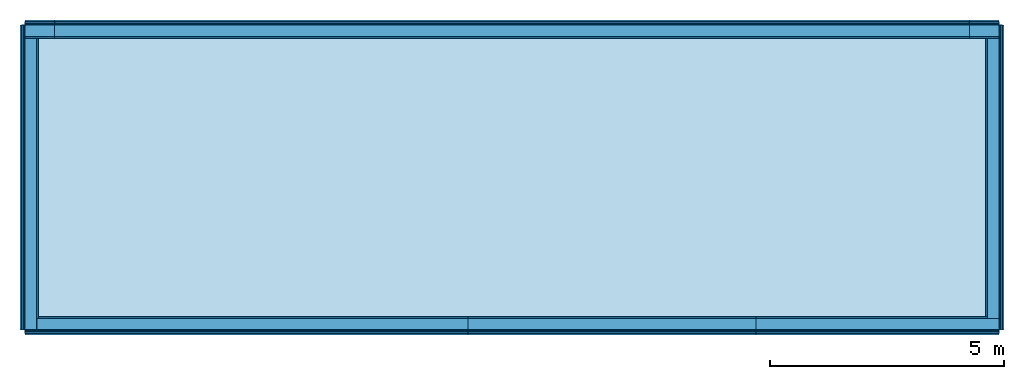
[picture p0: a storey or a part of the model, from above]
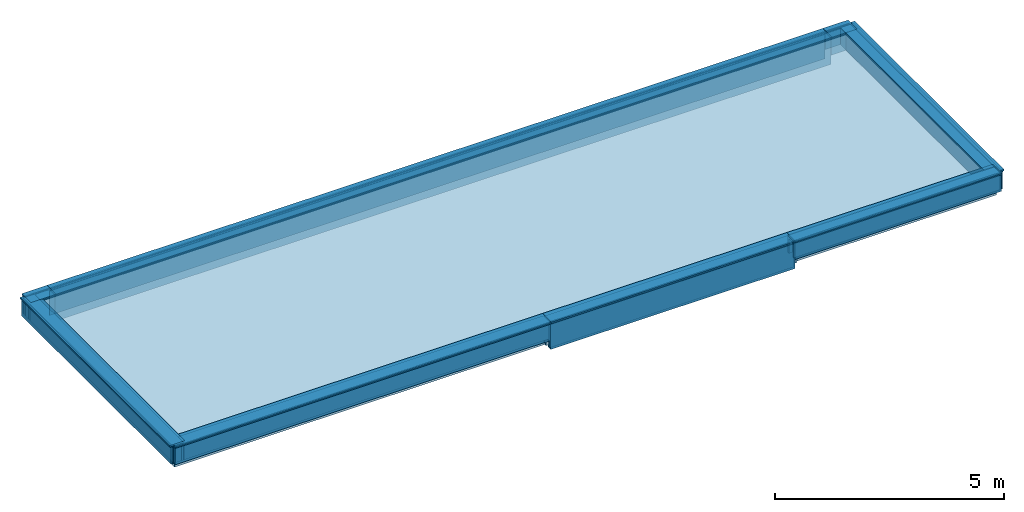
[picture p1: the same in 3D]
Properties of the parts of a building model (IFC2X3)

# File
Description: ViewDefinition [CoordinationView_V2.0], Option [Drawing Scale: 100.000000], Option [Global Unique Identifiers (GUID): Keep existing], Option [Elements to export: Visible elements (on all stories)], Option [Partial Structure Display: Entire Model], Option [IFC Domain: All], Option [Structural Function: All Elements], Option [Convert Grid elements: On], Option [Convert IFC Annotations and ARCHICAD 2D elements: Off], Option [Convert 2D symbols of Doors and Windows: Off], Option [Explode Composite and Complex Profile elements into parts: Off], Option [Export geometries that Participates in Collision Detection only: Off], Option [Multi-skin complex geometries: Building element parts], Option [Elements in Solid Element Operations: Extruded/revolved], Option [Elements with junctions: Extruded/revolved without junctions], Option [Slabs with slanted edge(s): Extruded], Option [Use legacy geometric methods as in Coordination View 1.0: Off], Option [IFC Site Geometry: As boundary representation (BRep)], Option [IFC Site Location: At Project Origin], Option [Curtain Wall export mode: Container Element], Option [Railing export mode: Single Element], Option [Stair export mode: Container Element], Option [Properties To Export: All properties], Option [Space containment: Off], Option [Bounding Box: Off], Option [Geometry to type objects: Off], Option [Element Properties: Off], Option [Property Type Element Parameter: Off], Option [Quantity Type Element Parameter: Off], Option [IFC Base Quantities: Off], Option [Window Door Lining and Panel Parameters: On], Option [IFC Space boundaries: Off], Option [ARCHICAD Zone Categories as IFC Space classification data: Off], Option [Element Classifications: Off]
File name: C:\Users\Thiago Mundim\Desktop\05_01 AC 21\Architectural File_R01.ifc
Time: 2017-08-08T17:24:18
Author: Ideia1 Arquitetura
Organization: Ideia1 Arquitetura
Written by: The EXPRESS Data Manager Version 5.02.0100.09 : 26 Sep 2013
Made in: IFC file generated by GRAPHISOFT ARCHICAD-64 21.0.0 INT FULL Windows version (IFC2x3 add-on version: 3005 INT FULL).
Authorization: Ideia1 Arquitetura

# IfcProject, Grove House
Description: Residential House; Phase: Schematic Design

# IfcSite, Grove Residential
RefLatitude: 24, 28, 0, 0; RefLongitude: 54, 25, 0, 0; RefElevation: 0 mm

# IfcBuildingStorey (4)
In: Building
Name | Elevation (mm)
Basement | -3060
Ground Floor | 0
First Floor | 3740
Roof Level | 6660

# IfcBuildingElementPart (84)
Name | In | Material
5 x Titanium Zinc | Ground Floor | Titanium Zinc
5 x Membrane - Rainproof | Ground Floor | Membrane - Rainproof
5 x Insulation - Plastic Soft | Ground Floor | Insulation - Plastic Soft
5 x Air Space | Ground Floor | Air Space
5 x Cement Board | Ground Floor | Cement Board
5 x External Render | Ground Floor | External Render
Titanium Zinc | First Floor | Titanium Zinc
Membrane - Rainproof | First Floor | Membrane - Rainproof
Insulation - Plastic Soft | First Floor | Insulation - Plastic Soft
Air Space | First Floor | Air Space
Cement Board | First Floor | Cement Board
External Render | First Floor | External Render
8 x Timber - Roof | Roof Level | Timber - Roof
8 x Insulation - Plastic Soft | Roof Level | Insulation - Plastic Soft
8 x Stone - Finish | Roof Level | Stone - Finish
8 x Membrane - Rainproof | Roof Level | Membrane - Rainproof
8 x Timber - External Cladding | Roof Level | Timber - External Cladding
8 x Air Space - Fixing Zone | Roof Level | Air Space - Fixing Zone

# IfcBuildingElementProxy: Fireplace-Traditional 21, FU - 004
In: Ground Floor
Material: Background
AC_Pset_RenovationAndPhasing - Renovation Status: Existing

# IfcColumn: Concrete - Structural 150 x 400 (40)
Material: Concrete - Structural
AC_Pset_RenovationAndPhasing - Renovation Status: Existing
Pset_ColumnCommon - Reference: Concrete - Structural 150 x 400
Name | In
13 x CRE - 001 | Basement
11 x CRE - 001 | Ground Floor
16 x CRE - 001 | First Floor

# IfcColumn: Concrete - Structural 150 x 785 (2)
In: Ground Floor
Material: Concrete - Structural
AC_Pset_RenovationAndPhasing - Renovation Status: Existing
Pset_ColumnCommon - Reference: Concrete - Structural 150 x 785

# IfcColumn: Concrete - Structural 200 x 400 (2)
In: Basement
Material: Concrete - Structural
AC_Pset_RenovationAndPhasing - Renovation Status: Existing
Pset_ColumnCommon - Reference: Concrete - Structural 200 x 400

# IfcColumn: Concrete - Structural 250 x 150 (2)
Material: Concrete - Structural
AC_Pset_RenovationAndPhasing - Renovation Status: Existing
Pset_ColumnCommon - Reference: Concrete - Structural 250 x 150
Name | In
CRE - 001 | Ground Floor
CRE - 001 | First Floor

# IfcColumn: Concrete - Structural 300 x 150, CRE - 001
In: First Floor
Material: Concrete - Structural
AC_Pset_RenovationAndPhasing - Renovation Status: Existing
Pset_ColumnCommon - Reference: Concrete - Structural 300 x 150

# IfcColumn: Concrete - Structural 400 x 150 (2)
In: Ground Floor
Material: Concrete - Structural
AC_Pset_RenovationAndPhasing - Renovation Status: Existing
Pset_ColumnCommon - Reference: Concrete - Structural 400 x 150

# IfcColumn: Concrete - Structural 570 x 150 (6)
Material: Concrete - Structural
AC_Pset_RenovationAndPhasing - Renovation Status: Existing
Pset_ColumnCommon - Reference: Concrete - Structural 570 x 150
Name | In
3 x CRE - 001 | Basement
3 x CRE - 001 | Ground Floor

# IfcDistributionElement: Basin Cabinet 21 (5)
Material: Background
AC_Pset_RenovationAndPhasing - Renovation Status: Existing
Name | In
3 x FU - 002 | Ground Floor
2 x FU - 002 | First Floor

# IfcDistributionElement: Cabinet Base Double Door 21 (5)
In: Ground Floor
Material: Background
AC_Pset_RenovationAndPhasing - Renovation Status: Existing

# IfcDistributionElement: Cabinet Base MultiDrawer 21, FU - 001
In: Ground Floor
Material: Background
AC_Pset_RenovationAndPhasing - Renovation Status: Existing

# IfcDistributionElement: Cabinet Base Single Door 21 (2)
In: Ground Floor
Material: Background
AC_Pset_RenovationAndPhasing - Renovation Status: Existing

# IfcDistributionElement: Cabinet Tall Single Door with Oven 21, FU - 001
In: Ground Floor
Material: Background
AC_Pset_RenovationAndPhasing - Renovation Status: Existing

# IfcDistributionElement: Cabinet Wall Double Door 21 (2)
In: Ground Floor
Material: Background
AC_Pset_RenovationAndPhasing - Renovation Status: Existing

# IfcDistributionElement: Cabinet Wall Single Door 21 (2)
In: Ground Floor
Material: Background
AC_Pset_RenovationAndPhasing - Renovation Status: Existing

# IfcDistributionElement: Cooktop Gas 21, FU - 001
In: Ground Floor
Material: Background
AC_Pset_RenovationAndPhasing - Renovation Status: Existing

# IfcDistributionElement: Mop Sink 21, FU - 001
In: Ground Floor
Material: Background
AC_Pset_RenovationAndPhasing - Renovation Status: Existing

# IfcDistributionElement: Multi-Basin Counter 21, FU - 002
In: First Floor
Material: Background
AC_Pset_RenovationAndPhasing - Renovation Status: Existing

# IfcDistributionElement: Rail Wired 02 20 (14)
Material: Background
AC_Pset_RenovationAndPhasing - Renovation Status: Existing
Name | In
7 x FU - 001 | Ground Floor
7 x FU - 001 | First Floor

# IfcDistributionElement: Shower Kit 21 (5)
Material: Background
AC_Pset_RenovationAndPhasing - Renovation Status: Existing
Name | In
2 x FU - 001 | Ground Floor
3 x FU - 001 | First Floor

# IfcDistributionElement: WC 21 (6)
Material: Background
AC_Pset_RenovationAndPhasing - Renovation Status: Existing
Name | In
3 x FU - 001 | Ground Floor
3 x FU - 001 | First Floor

# IfcDoor: Door 21 (2)
In: First Floor
Type - OperationType: SINGLE_SWING_LEFT; ParameterTakesPrecedence: no; Sizeable: no
Type - Door Lining Properties - LiningThickness: 40 mm; LiningOffset: 0 mm; CasingThickness: 100 mm; CasingDepth: 19 mm
Type - Door Panel Properties - Panel 1 - PanelDepth: 40 mm; PanelOperation: SWINGING; PanelWidth: 1; PanelPosition: MIDDLE
OverallHeight: 2140 mm; OverallWidth: 880 mm; Material: Background (11), Air Space (2), Foreground, Rigid Insulation, Batt Insulation
Pset_DoorCommon - ThermalTransmittance: 0; GlazingAreaFraction: 0
AC_Pset_RenovationAndPhasing - Renovation Status: Existing

# IfcDoor: Door 21, D.03
In: Ground Floor
Type - OperationType: SINGLE_SWING_RIGHT; ParameterTakesPrecedence: no; Sizeable: no
Type - Door Lining Properties - LiningDepth: 115 mm; LiningThickness: 70 mm; LiningOffset: 235 mm
Type - Door Panel Properties - Panel 1 - PanelDepth: 40 mm; PanelOperation: SWINGING; PanelWidth: 1; PanelPosition: MIDDLE
OverallHeight: 2700 mm; OverallWidth: 1000 mm; Material: Background (11), Air Space (2), Foreground, Rigid Insulation, Batt Insulation
Pset_DoorCommon - ThermalTransmittance: 0; GlazingAreaFraction: 1.99293
AC_Pset_RenovationAndPhasing - Renovation Status: Existing

# IfcDoor: Door 21 (7)
Type - OperationType: SINGLE_SWING_RIGHT; ParameterTakesPrecedence: no; Sizeable: no
Type - Door Lining Properties - LiningThickness: 40 mm; LiningOffset: 0 mm; CasingThickness: 100 mm; CasingDepth: 19 mm
Type - Door Panel Properties - Panel 1 - PanelDepth: 40 mm; PanelOperation: SWINGING; PanelWidth: 1; PanelPosition: MIDDLE
OverallHeight: 2140 mm; Material: Background (11), Air Space (2), Foreground, Rigid Insulation, Batt Insulation
Pset_DoorCommon - ThermalTransmittance: 0; GlazingAreaFraction: 0
AC_Pset_RenovationAndPhasing - Renovation Status: Existing
Name | In | OverallWidth (mm)
2 x D.02 | Ground Floor | 1080
4 x D.01 | Ground Floor | 880
D.01 | First Floor | 880

# IfcDoor: Door 21 (2)
Type - OperationType: SINGLE_SWING_RIGHT; ParameterTakesPrecedence: no; Sizeable: no
Type - Door Lining Properties - LiningThickness: 40 mm; LiningOffset: 150 mm; CasingThickness: 100 mm; CasingDepth: 19 mm
Type - Door Panel Properties - Panel 1 - PanelDepth: 40 mm; PanelOperation: SWINGING; PanelWidth: 1; PanelPosition: MIDDLE
OverallHeight: 2140 mm; Material: Background (11), Air Space (2), Foreground, Rigid Insulation, Batt Insulation
Pset_DoorCommon - ThermalTransmittance: 0; GlazingAreaFraction: 0
AC_Pset_RenovationAndPhasing - Renovation Status: Existing
Name | In | OverallWidth (mm)
D.02 | Basement | 1080
D.01 | First Floor | 880

# IfcDoor: Exterior Sliding Door 21, D.01
In: First Floor
Type - OperationType: SLIDING_TO_LEFT; ParameterTakesPrecedence: no; Sizeable: no
Type - Door Lining Properties - CasingThickness: 100 mm; CasingDepth: 19 mm
Type - Door Panel Properties - Panel 1 - PanelDepth: 40 mm; PanelOperation: SLIDING; PanelWidth: 1; PanelPosition: MIDDLE
OverallHeight: 2100 mm; OverallWidth: 800 mm; Material: Background (11), Air Space, Foreground, Rigid Insulation, Batt Insulation
Pset_DoorCommon - ThermalTransmittance: 0; GlazingAreaFraction: 0
AC_Pset_RenovationAndPhasing - Renovation Status: Existing

# IfcDoor: Exterior Sliding Door 21, D.01
In: First Floor
Type - OperationType: SLIDING_TO_RIGHT; ParameterTakesPrecedence: no; Sizeable: no
Type - Door Lining Properties - CasingThickness: 100 mm; CasingDepth: 19 mm
Type - Door Panel Properties - Panel 1 - PanelDepth: 40 mm; PanelOperation: SLIDING; PanelWidth: 1; PanelPosition: MIDDLE
OverallHeight: 2100 mm; OverallWidth: 800 mm; Material: Background (11), Air Space, Foreground, Rigid Insulation, Batt Insulation
Pset_DoorCommon - ThermalTransmittance: 0; GlazingAreaFraction: 0
AC_Pset_RenovationAndPhasing - Renovation Status: Existing

# IfcDoor: Pivot Door 21, D.05
In: Ground Floor
Type - OperationType: USERDEFINED; ParameterTakesPrecedence: no; Sizeable: no
OverallHeight: 2700 mm; OverallWidth: 1300 mm; Material: Background (11), Air Space (2), Foreground, Rigid Insulation, Batt Insulation
Pset_DoorCommon - ThermalTransmittance: 0; GlazingAreaFraction: 0
AC_Pset_RenovationAndPhasing - Renovation Status: Existing

# IfcDoor: Sliding Door 21 (8)
Type - OperationType: USERDEFINED; ParameterTakesPrecedence: no; Sizeable: no
Material: Background (11), Air Space (2), Foreground, Rigid Insulation, Batt Insulation
Pset_DoorCommon - ThermalTransmittance: 0
AC_Pset_RenovationAndPhasing - Renovation Status: Existing
Name | In | OverallHeight (mm) | OverallWidth (mm) | GlazingAreaFraction
D.10 | Basement | 2500 | 3550 | 0
D.11 | Ground Floor | 2700 | 4500 | 10.2718
D.09 | Ground Floor | 2700 | 3000 | 6.7298
D.12 | First Floor | 2300 | 6145 | 11.9386
2 x D.06 | First Floor | 2200 | 2500 | 4.3848
D.06 | First Floor | 2500 | 2500 | 5.0328
D.13 | First Floor | 2500 | 6325 | 13.4791

# IfcDoor: Vertical Sliding Garage Door 21 (2)
In: Basement
Type - OperationType: ROLLINGUP; ParameterTakesPrecedence: no; Sizeable: no
Type - Door Lining Properties - LiningThickness: 50 mm; LiningOffset: 300 mm
Type - Door Panel Properties - Panel 1 - PanelDepth: 40 mm; PanelOperation: ROLLINGUP; PanelWidth: 1; PanelPosition: MIDDLE
OverallHeight: 2500 mm; Material: Background (8), Air Space, Batt Insulation, Rigid Insulation
Pset_DoorCommon - ThermalTransmittance: 0; GlazingAreaFraction: 0
AC_Pset_RenovationAndPhasing - Renovation Status: Existing
Name | OverallWidth (mm)
D.07 | 2750
D.08 | 2915

# IfcSlab: GENERIC - STRUCTURAL 250 (2)
In: First Floor
Type - PredefinedType: FLOOR
Material: GENERIC - STRUCTURAL 250 mm
AC_Pset_RenovationAndPhasing - Renovation Status: Existing

# IfcSlab: Grass Paver 70, SLA - 001
In: Basement
Type - PredefinedType: FLOOR
Material: Grass Paver 70 mm
AC_Pset_RenovationAndPhasing - Renovation Status: Existing

# IfcSlab: IFS - 001 700, SLA - 001
In: Basement
Type - PredefinedType: FLOOR
Material: Polished Concrete 10 mm, Screed 40 mm, Concrete - Structural 150 mm, Gravel 500 mm
AC_Pset_RenovationAndPhasing - Renovation Status: Existing

# IfcSlab: IFS - 002 260 (2)
In: First Floor
Type - PredefinedType: FLOOR
Material: Screed 50 mm, Membrane - Rainproof 10 mm, Insulation - Plastic Hard 50 mm, Concrete - Structural 150 mm
AC_Pset_RenovationAndPhasing - Renovation Status: Existing

# IfcSlab: IFS - 003 410, SLA - 001
In: First Floor
Type - PredefinedType: FLOOR
Material: Timber - Floor 50 mm, Air Space - Fixing Zone 150 mm, Membrane - Rainproof 10 mm, Insulation - Plastic Hard 50 mm, Concrete - Structural 150 mm
AC_Pset_RenovationAndPhasing - Renovation Status: Existing

# IfcSlab: IFS - 004 560, SLA - 001
In: First Floor
Type - PredefinedType: FLOOR
Material: Timber - Floor 50 mm, Air Space - Fixing Zone 300 mm, Membrane - Rainproof 10 mm, Insulation - Plastic Hard 50 mm, Concrete - Structural 150 mm
AC_Pset_RenovationAndPhasing - Renovation Status: Existing

# IfcSlab: IFS - 005 580, SLA - 001
In: Roof Level
Type - PredefinedType: FLOOR
Material: Gravel 370 mm, Screed 50 mm, Membrane - Rainproof 10 mm, Insulation - Plastic Soft 50 mm, Concrete - Structural 100 mm
AC_Pset_RenovationAndPhasing - Renovation Status: Existing

# IfcSlab: IFS - 006 210 (2)
Type - PredefinedType: FLOOR
Material: Polished Concrete 10 mm, Screed 50 mm, Concrete - Structural 150 mm
AC_Pset_RenovationAndPhasing - Renovation Status: Existing
Name | In
SLA - 001 | Ground Floor
SLA - 001 | First Floor

# IfcSlab: IFS - 007 160 (4)
In: Ground Floor
Type - PredefinedType: FLOOR
Material: Polished Concrete 10 mm, Screed 50 mm, Concrete - Structural 100 mm
AC_Pset_RenovationAndPhasing - Renovation Status: Existing

# IfcSlab: IFS - 008 210 (6)
Type - PredefinedType: FLOOR
Material: Floor Tiles 20 mm, Screed 40 mm, Concrete - Structural 150 mm
AC_Pset_RenovationAndPhasing - Renovation Status: Existing
Name | In
3 x SLA - 001 | Ground Floor
3 x SLA - 001 | First Floor

# IfcSlab: IFS - 009 260 (2)
In: First Floor
Type - PredefinedType: FLOOR
Material: Timber - Floor 50 mm, Membrane - Rainproof 10 mm, Insulation - Plastic Hard 50 mm, Concrete - Structural 150 mm
AC_Pset_RenovationAndPhasing - Renovation Status: Existing

# IfcSlab: Stone - Finish 40, SLA - 001
In: Ground Floor
Type - PredefinedType: FLOOR
Material: Stone - Finish 40 mm
AC_Pset_RenovationAndPhasing - Renovation Status: Existing

# IfcSlab: Timber - External Cladding 70 (2)
In: First Floor
Type - PredefinedType: FLOOR
Material: Timber - External Cladding 70 mm
AC_Pset_RenovationAndPhasing - Renovation Status: Existing

# IfcSlab: Timber - Floor 100, SLA - 001
In: Ground Floor
Type - PredefinedType: FLOOR
Material: Timber - Floor 100 mm
AC_Pset_RenovationAndPhasing - Renovation Status: Existing

# IfcWall: Detail 01 135 x 150 (6)
AC_Pset_RenovationAndPhasing - Renovation Status: Existing
Name | In
4 x SW - 004 | Ground Floor
SW - 005 | Ground Floor
SW - 004 | First Floor

# IfcWall: Parapet Wall 395 x 505 (6)
In: Roof Level
AC_Pset_RenovationAndPhasing - Renovation Status: Existing
Name
2 x SW - 003
SW - 004
2 x SW - 005
SW - 002

# IfcWall: Parapet Wall 395 x 745 (2)
In: Roof Level
AC_Pset_RenovationAndPhasing - Renovation Status: Existing
Name
SW - 005
SW - 003

# IfcWallStandardCase: Concrete Block 150, SW - 001
In: Basement
Material: Concrete Block 150 mm
AC_Pset_RenovationAndPhasing - Renovation Status: Existing

# IfcWallStandardCase: EWF - 001 300 (4)
Material: External Render 20 mm, Cement Board 10 mm, Air Space 35 mm, Insulation - Plastic Soft 50 mm, Concrete Block 150 mm, Air Space - Fixing Zone 10 mm, Gypsum Plasterboard 12.5 mm, Gypsum Plasterboard 12.5 mm
AC_Pset_RenovationAndPhasing - Renovation Status: Existing
Name | In
SW - 001 | Ground Floor
SW - 003 | Ground Floor
SW - 003 | First Floor
SW - 004 | First Floor

# IfcWallStandardCase: EWF - 002 300 (12)
Material: Timber - External Cladding 40 mm, Air Space - Fixing Zone 25 mm, Insulation - Plastic Soft 50 mm, Concrete Block 150 mm, Air Space - Fixing Zone 10 mm, Gypsum Plasterboard 12.5 mm, Gypsum Plasterboard 12.5 mm
AC_Pset_RenovationAndPhasing - Renovation Status: Existing
Name | In
3 x SW - 001 | Ground Floor
3 x SW - 002 | Ground Floor
6 x SW - 003 | First Floor

# IfcWallStandardCase: EWF - 003 100 (12)
In: Ground Floor
Material: External Render 20 mm, Cement Board 10 mm, Air Space - Frame 70 mm
AC_Pset_RenovationAndPhasing - Renovation Status: Existing
Name
8 x SW - 001
4 x SW - 002

# IfcWallStandardCase: EWF - 004 235 (7)
Material: Insulation - Plastic Soft 50 mm, Concrete Block 150 mm, Air Space - Fixing Zone 10 mm, Gypsum Plasterboard 12.5 mm, Gypsum Plasterboard 12.5 mm
AC_Pset_RenovationAndPhasing - Renovation Status: Existing
Name | In
3 x SW - 001 | Ground Floor
2 x SW - 002 | Ground Floor
2 x SW - 004 | First Floor

# IfcWallStandardCase: EWF - 005 290 (3)
In: Ground Floor
Material: External Render 20 mm, Cement Board 10 mm, Air Space - Fixing Zone 25 mm, Insulation - Plastic Soft 50 mm, Concrete Block 150 mm, Brick - Fireplace 35 mm
AC_Pset_RenovationAndPhasing - Renovation Status: Existing
Name
SW - 001
SW - 002
SW - 003

# IfcWallStandardCase: EWF - 006 220, SW - 004
In: Ground Floor
Material: Brick - Fireplace 35 mm, Concrete Block 150 mm, Air Space - Fixing Zone 10 mm, Gypsum Plasterboard 12.5 mm, Gypsum Plasterboard 12.5 mm
AC_Pset_RenovationAndPhasing - Renovation Status: Existing

# IfcWallStandardCase: EWF - 007 110 (12)
Material: Timber - External Cladding 40 mm, Air Space - Fixing Zone 70 mm
AC_Pset_RenovationAndPhasing - Renovation Status: Existing
Name | In
3 x SW - 002 | Ground Floor
2 x SW - 001 | First Floor
5 x SW - 002 | First Floor
2 x SW - 003 | First Floor

# IfcWallStandardCase: EWF - 009 300 (2)
In: Basement
Material: Stonework wall 50 mm, Air Space 15 mm, Insulation - Plastic Soft 50 mm, Concrete Block 150 mm, Air Space - Fixing Zone 10 mm, Gypsum Plasterboard 12.5 mm, Gypsum Plasterboard 12.5 mm
AC_Pset_RenovationAndPhasing - Renovation Status: Existing
Name
SW - 001
SW - 004

# IfcWallStandardCase: EWF - 010 265 (13)
Material: Stonework wall 50 mm, Air Space 65 mm, Concrete Block 150 mm
AC_Pset_RenovationAndPhasing - Renovation Status: Existing
Name | In
2 x SW - 003 | Basement
2 x SW - 004 | Basement
2 x SW - 001 | Basement
2 x SW - 002 | Basement
SW - 005 | Basement
SW - 001 | Ground Floor
SW - 002 | Ground Floor
SW - 003 | Ground Floor
SW - 004 | Ground Floor

# IfcWallStandardCase: EWF - 011 235 (4)
In: Basement
Material: Insulation - Plastic Soft 50 mm, Concrete Block 150 mm, Air Space - Fixing Zone 10 mm, Gypsum Plasterboard 12.5 mm, Gypsum Plasterboard 12.5 mm
AC_Pset_RenovationAndPhasing - Renovation Status: Existing
Name
2 x SW - 005
SW - 001
SW - 002

# IfcWallStandardCase: EWF - 012 100 (9)
In: Ground Floor
Material: External Render 20 mm, Cement Board 10 mm, Air Space 35 mm, Air Space - Fixing Zone 10 mm, Gypsum Plasterboard 12.5 mm, Gypsum Plasterboard 12.5 mm
AC_Pset_RenovationAndPhasing - Renovation Status: Existing

# IfcWallStandardCase: IF-001 25 (12)
Material: Gypsum Plasterboard 12.5 mm, Gypsum Plasterboard 12.5 mm
AC_Pset_RenovationAndPhasing - Renovation Status: Existing
Name | In
2 x SW - 001 | Ground Floor
SW - 001 | First Floor
2 x SW - 002 | First Floor
SW - 003 | First Floor
SW - 009 | First Floor
SW - 010 | First Floor
2 x SW - 011 | First Floor
SW - 012 | First Floor
SW - 013 | First Floor

# IfcWallStandardCase: IF-002 25 (7)
In: First Floor
Material: Wall Tiles 12.5 mm, Gypsum Plasterboard 12.5 mm
AC_Pset_RenovationAndPhasing - Renovation Status: Existing
Name
SW - 003
2 x SW - 004
SW - 005
SW - 006
SW - 007
SW - 008

# IfcWallStandardCase: IWF-001 150 (6)
Material: Gypsum Plasterboard 12.5 mm, Gypsum Plasterboard 12.5 mm, Air Space - Frame 50 mm, Insulation - Mineral Soft 50 mm, Gypsum Plasterboard 12.5 mm, Gypsum Plasterboard 12.5 mm
AC_Pset_RenovationAndPhasing - Renovation Status: Existing
Name | In
2 x SW - 001 | Ground Floor
4 x SW - 001 | First Floor

# IfcWallStandardCase: IWF-002 150 (10)
Material: Wall Tiles 12.5 mm, Gypsum Plasterboard - Waterproof 12.5 mm, Air Space - Frame 50 mm, Insulation - Mineral Soft 50 mm, Gypsum Plasterboard 12.5 mm, Gypsum Plasterboard 12.5 mm
AC_Pset_RenovationAndPhasing - Renovation Status: Existing
Name | In
5 x SW - 001 | Ground Floor
5 x SW - 001 | First Floor

# IfcWallStandardCase: IWF-003 150 (4)
Material: Wall Tiles 12.5 mm, Gypsum Plasterboard - Waterproof 12.5 mm, Air Space - Frame 50 mm, Insulation - Mineral Soft 50 mm, Gypsum Plasterboard - Waterproof 12.5 mm, Wall Tiles 12.5 mm
AC_Pset_RenovationAndPhasing - Renovation Status: Existing
Name | In
2 x SW - 001 | Ground Floor
SW - 002 | Ground Floor
SW - 001 | First Floor

# IfcWallStandardCase: IWF-004 200, SW - 001
In: Ground Floor
Material: Wall Tiles 12.5 mm, Gypsum Plasterboard - Waterproof 12.5 mm, Air Space - Frame 100 mm, Insulation - Mineral Soft 50 mm, Gypsum Plasterboard - Waterproof 12.5 mm, Wall Tiles 12.5 mm
AC_Pset_RenovationAndPhasing - Renovation Status: Existing

# IfcWallStandardCase: IWF-005 210, SW - 001
In: Ground Floor
Material: Wall Tiles 12.5 mm, Gypsum Plasterboard - Waterproof 12.5 mm, Air Space - Frame 100 mm, Insulation - Mineral Soft 50 mm, Air Space - Fixing Zone 10 mm, Gypsum Plasterboard 12.5 mm, Gypsum Plasterboard 12.5 mm
AC_Pset_RenovationAndPhasing - Renovation Status: Existing

# IfcWallStandardCase: IWF-006 150 (7)
Material: Wall Tiles 12.5 mm, Gypsum Plasterboard - Waterproof 12.5 mm, Air Space - Frame 100 mm, Gypsum Plasterboard - Waterproof 12.5 mm, Wall Tiles 12.5 mm
AC_Pset_RenovationAndPhasing - Renovation Status: Existing
Name | In
SW - 002 | Basement
2 x SW - 005 | Basement
SW - 004 | Basement
3 x SW - 002 | Ground Floor

# IfcWallStandardCase: IWF-007 150 (2)
In: Basement
Material: Gypsum Plasterboard 12.5 mm, Gypsum Plasterboard 12.5 mm, Air Space - Frame 100 mm, Gypsum Plasterboard 12.5 mm, Gypsum Plasterboard 12.5 mm
AC_Pset_RenovationAndPhasing - Renovation Status: Existing

# IfcWallStandardCase: Stonework wall 200 (3)
In: Basement
Material: Stonework wall 200 mm
AC_Pset_RenovationAndPhasing - Renovation Status: Existing
Name
2 x SW - 001
SW - 002

# IfcWindow: Window 21 (6)
Type - OperationType: DOUBLE_PANEL_VERTICAL; ParameterTakesPrecedence: no; Sizeable: no
Type - Window Lining Properties - LiningDepth: 50 mm; LiningThickness: 50 mm; MullionThickness: 50 mm; FirstMullionOffset: 0.5
Type - Window Panel Properties - Panel 1 - OperationType: SLIDINGHORIZONTAL; PanelPosition: LEFT; FrameDepth: 50 mm; FrameThickness: 50 mm
Type - Window Panel Properties - Panel 2 - OperationType: SLIDINGHORIZONTAL; PanelPosition: RIGHT; FrameDepth: 50 mm; FrameThickness: 50 mm
Material: Background (9), Air Space (2), Rigid Insulation, Batt Insulation
Pset_WindowCommon - ThermalTransmittance: 0
AC_Pset_RenovationAndPhasing - Renovation Status: Existing
Name | In | OverallHeight (mm) | OverallWidth (mm) | GlazingAreaFraction
W.06 | Ground Floor | 1700 | 1200 | 1.425
W.08 | Ground Floor | 1700 | 1500 | 1.875
W.04 | Ground Floor | 1700 | 1000 | 1.125
2 x W.03 | First Floor | 1000 | 1000 | 0.6
W.02 | First Floor | 1000 | 900 | 0.52

# IfcWindow: Window 21 (3)
In: Ground Floor
Type - OperationType: DOUBLE_PANEL_VERTICAL; ParameterTakesPrecedence: no; Sizeable: no
Type - Window Lining Properties - LiningDepth: 50 mm; LiningThickness: 50 mm; MullionThickness: 50 mm; FirstMullionOffset: 0.5
Type - Window Panel Properties - Panel 1 - OperationType: SLIDINGHORIZONTAL; PanelPosition: RIGHT; FrameDepth: 50 mm; FrameThickness: 50 mm
Type - Window Panel Properties - Panel 2 - OperationType: SLIDINGHORIZONTAL; PanelPosition: LEFT; FrameDepth: 50 mm; FrameThickness: 50 mm
Material: Background (9), Air Space (2), Rigid Insulation, Batt Insulation
Pset_WindowCommon - ThermalTransmittance: 0
AC_Pset_RenovationAndPhasing - Renovation Status: Existing
Name | OverallHeight (mm) | OverallWidth (mm) | GlazingAreaFraction
W.10 | 2700 | 3000 | 6.875
W.09 | 500 | 2500 | 0.675
W.07 | 500 | 1500 | 0.375

# IfcWindow: Window 21 (2)
In: Ground Floor
Type - OperationType: SINGLE_PANEL; ParameterTakesPrecedence: no; Sizeable: no
Type - Window Lining Properties - LiningDepth: 50 mm; LiningThickness: 50 mm
Type - Window Panel Properties - Panel 1 - OperationType: FIXEDCASEMENT; PanelPosition: MIDDLE
OverallHeight: 2500 mm; OverallWidth: 800 mm; Material: Background (9), Air Space (2), Rigid Insulation, Batt Insulation
Pset_WindowCommon - ThermalTransmittance: 0; GlazingAreaFraction: 1.68
AC_Pset_RenovationAndPhasing - Renovation Status: Existing
